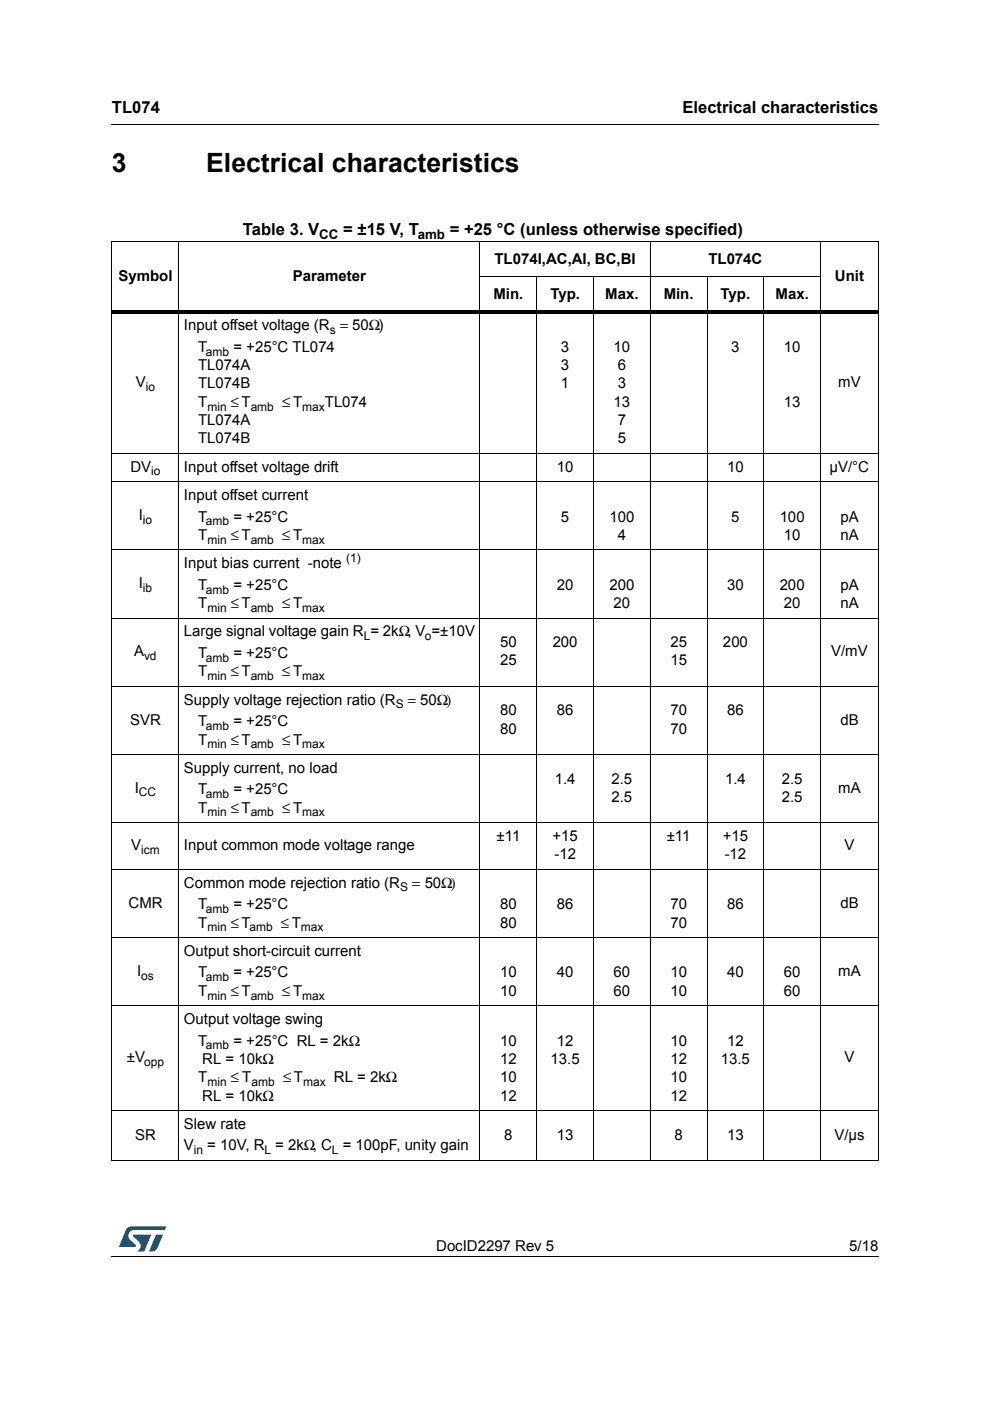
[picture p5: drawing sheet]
<svg xmlns="http://www.w3.org/2000/svg" width="210mm" height="297mm" viewBox="0 0 210 297" stroke-linecap="round" stroke-linejoin="round" font-family="sans-serif">
<defs><g id="words">
<g font-size="5.6">
<text x="23.7" y="36.4">3</text>
<text x="43.7" y="36.4">Electrical characteristics</text>
</g>
<g font-size="3.5">
<text x="23.7" y="23.9">TL074</text>
<text x="144.7" y="23.9">Electrical characteristics</text>
<text x="51.5" y="49.8">Table 3. V</text>
<text x="72.8" y="49.8">= ±15 V, T</text>
<text x="95.4" y="49.8">= +25 °C (unless otherwise specified)</text>
</g>
<g font-size="3.2">
<text x="25.1" y="59.6">Symbol</text>
<text x="62.1" y="59.6">Parameter</text>
<text x="104.8" y="55.9">TL074I,AC,AI, BC,BI</text>
<text x="150.2" y="55.9">TL074C</text>
<text x="177" y="59.6">Unit</text>
<text x="104.6" y="63.3">Min.</text>
<text x="116.7" y="63.3">Typ.</text>
<text x="128.3" y="63.3">Max.</text>
<text x="140.7" y="63.3">Min.</text>
<text x="152.8" y="63.3">Typ.</text>
<text x="164.5" y="63.3">Max.</text>
<text x="39" y="70">Input offset voltage (R = 50Ω)</text>
<text x="42" y="74.6">T</text>
<text x="49.5" y="74.6">= +25°C TL074</text>
<text x="118.9" y="74.6">3</text>
<text x="130.1" y="74.6">10</text>
<text x="155" y="74.6">3</text>
<text x="166.2" y="74.6">10</text>
<text x="28.8" y="82">V</text>
<text x="42" y="78.5">TL074A</text>
<text x="42" y="82.4">TL074B</text>
<text x="118.9" y="78.5">3</text>
<text x="118.9" y="82.4">1</text>
<text x="131" y="78.5">6</text>
<text x="131" y="82.4">3</text>
<text x="177.7" y="82">mV</text>
<text x="42" y="86.2">T</text>
<text x="48.9" y="86.2">≤ T</text>
<text x="59.8" y="86.2">≤ T</text>
<text x="68.9" y="86.2">TL074</text>
<text x="130.1" y="86.2">13</text>
<text x="166.2" y="86.2">13</text>
<text x="42" y="90.1">TL074A</text>
<text x="42" y="94">TL074B</text>
<text x="131" y="90.1">7</text>
<text x="131" y="94">5</text>
<text x="27.7" y="100">DV</text>
<text x="39" y="100">Input offset voltage drift</text>
<text x="118.1" y="100">10</text>
<text x="154.2" y="100">10</text>
<text x="175.9" y="100">µV/°C</text>
<text x="39" y="106">Input offset current</text>
<text x="29.4" y="110.2">I</text>
<text x="42" y="110.6">T</text>
<text x="49.5" y="110.6">= +25°C</text>
<text x="118.9" y="110.6">5</text>
<text x="129.2" y="110.6">100</text>
<text x="155" y="110.6">5</text>
<text x="165.3" y="110.6">100</text>
<text x="178.2" y="110.6">pA</text>
<text x="42" y="114.5">T</text>
<text x="48.9" y="114.5">≤ T</text>
<text x="59.8" y="114.5">≤ T</text>
<text x="131" y="114.5">4</text>
<text x="166.2" y="114.5">10</text>
<text x="178.2" y="114.5">nA</text>
<text x="29.4" y="124.7">I</text>
<text x="39" y="120.5">Input bias current -note</text>
<text x="42" y="125.1">T</text>
<text x="49.5" y="125.1">= +25°C</text>
<text x="118.1" y="125.1">20</text>
<text x="129.2" y="125.1">200</text>
<text x="154.2" y="125.1">30</text>
<text x="165.3" y="125.1">200</text>
<text x="178.2" y="125.1">pA</text>
<text x="42" y="128.9">T</text>
<text x="48.9" y="128.9">≤ T</text>
<text x="59.8" y="128.9">≤ T</text>
<text x="130.1" y="128.9">20</text>
<text x="166.2" y="128.9">20</text>
<text x="178.2" y="128.9">nA</text>
<text x="39" y="134.9">Large signal voltage gain R = 2kΩ, V =±10V</text>
<text x="106" y="137.2">50</text>
<text x="117.2" y="137.2">200</text>
<text x="142.1" y="137.2">25</text>
<text x="153.3" y="137.2">200</text>
<text x="28.5" y="139.1">A</text>
<text x="42" y="143.4">T</text>
<text x="42" y="139.5">T</text>
<text x="48.9" y="143.4">≤ T</text>
<text x="49.5" y="139.5">= +25°C</text>
<text x="59.8" y="143.4">≤ T</text>
<text x="106" y="141.1">25</text>
<text x="142.1" y="141.1">15</text>
<text x="176.2" y="139.1">V/mV</text>
<text x="39" y="149.4">Supply voltage rejection ratio (R</text>
<text x="86.5" y="149.4">= 50Ω)</text>
<text x="27.6" y="153.6">SVR</text>
<text x="42" y="154">T</text>
<text x="49.5" y="154">= +25°C</text>
<text x="106" y="151.7">80</text>
<text x="106" y="155.6">80</text>
<text x="118.1" y="151.7">86</text>
<text x="142.1" y="151.7">70</text>
<text x="142.1" y="155.6">70</text>
<text x="154.2" y="151.7">86</text>
<text x="178.2" y="153.6">dB</text>
<text x="42" y="157.9">T</text>
<text x="48.9" y="157.9">≤ T</text>
<text x="59.8" y="157.9">≤ T</text>
<text x="39" y="163.9">Supply current, no load</text>
<text x="117.6" y="166.1">1.4</text>
<text x="129.6" y="166.1">2.5</text>
<text x="153.7" y="166.1">1.4</text>
<text x="165.8" y="166.1">2.5</text>
<text x="28.6" y="168.1">I</text>
<text x="42" y="172.3">T</text>
<text x="42" y="168.4">T</text>
<text x="48.9" y="172.3">≤ T</text>
<text x="49.5" y="168.4">= +25°C</text>
<text x="59.8" y="172.3">≤ T</text>
<text x="129.6" y="170">2.5</text>
<text x="165.8" y="170">2.5</text>
<text x="177.7" y="168.1">mA</text>
<text x="105.3" y="178.3">±11</text>
<text x="117.1" y="178.3">+15</text>
<text x="141.4" y="178.3">±11</text>
<text x="153.2" y="178.3">+15</text>
<text x="27.8" y="180.3">V</text>
<text x="39" y="180.3">Input common mode voltage range</text>
<text x="117.5" y="182.2">-12</text>
<text x="153.6" y="182.2">-12</text>
<text x="179" y="180.3">V</text>
<text x="39" y="188.2">Common mode rejection ratio (R</text>
<text x="87.4" y="188.2">= 50Ω)</text>
<text x="27.2" y="192.4">CMR</text>
<text x="42" y="196.7">T</text>
<text x="42" y="192.8">T</text>
<text x="48.9" y="196.7">≤ T</text>
<text x="49.5" y="192.8">= +25°C</text>
<text x="59.6" y="196.7">≤ T</text>
<text x="106" y="192.8">80</text>
<text x="106" y="196.7">80</text>
<text x="118.1" y="192.8">86</text>
<text x="142.1" y="192.8">70</text>
<text x="142.1" y="196.7">70</text>
<text x="154.2" y="192.8">86</text>
<text x="178.2" y="192.4">dB</text>
<text x="39" y="202.6">Output short-circuit current</text>
<text x="29.1" y="206.9">I</text>
<text x="42" y="207.2">T</text>
<text x="49.5" y="207.2">= +25°C</text>
<text x="106" y="207.2">10</text>
<text x="118.1" y="207.2">40</text>
<text x="130.1" y="207.2">60</text>
<text x="142.1" y="207.2">10</text>
<text x="154.2" y="207.2">40</text>
<text x="166.2" y="207.2">60</text>
<text x="177.7" y="206.9">mA</text>
<text x="42" y="211.1">T</text>
<text x="48.9" y="211.1">≤ T</text>
<text x="59.8" y="211.1">≤ T</text>
<text x="106" y="211.1">10</text>
<text x="130.1" y="211.1">60</text>
<text x="142.1" y="211.1">10</text>
<text x="166.2" y="211.1">60</text>
<text x="39" y="217.1">Output voltage swing</text>
<text x="42" y="221.7">T</text>
<text x="49.5" y="221.7">= +25°C RL = 2kΩ</text>
<text x="106" y="221.7">10</text>
<text x="118.1" y="221.7">12</text>
<text x="142.1" y="221.7">10</text>
<text x="154.2" y="221.7">12</text>
<text x="26.9" y="225.2">±V</text>
<text x="42.9" y="225.6">RL = 10kΩ</text>
<text x="106" y="225.6">12</text>
<text x="116.7" y="225.6">13.5</text>
<text x="142.1" y="225.6">12</text>
<text x="152.8" y="225.6">13.5</text>
<text x="179" y="225.2">V</text>
<text x="42" y="229.5">T</text>
<text x="42.9" y="233.3">RL = 10kΩ</text>
<text x="48.9" y="229.5">≤ T</text>
<text x="60" y="229.5">≤ T</text>
<text x="70.8" y="229.5">RL = 2kΩ</text>
<text x="106" y="229.5">10</text>
<text x="106" y="233.3">12</text>
<text x="142.1" y="229.5">10</text>
<text x="142.1" y="233.3">12</text>
<text x="39" y="239.4">Slew rate</text>
<text x="28.6" y="241.6">SR</text>
<text x="39" y="243.9">V</text>
<text x="43.9" y="243.9">= 10V, R</text>
<text x="58.4" y="243.9">= 2kΩ, C</text>
<text x="72.7" y="243.9">= 100pF, unity gain</text>
<text x="106.9" y="241.6">8</text>
<text x="118.1" y="241.6">13</text>
<text x="143" y="241.6">8</text>
<text x="154.2" y="241.6">13</text>
<text x="176.9" y="241.6">V/µs</text>
<text x="92.5" y="265.1">DocID2297 Rev 5</text>
<text x="180.1" y="265.1">5/18</text>
</g>
<g font-size="2.8">
<text x="67.7" y="50.7">CC</text>
<text x="88.6" y="50.7">amb</text>
</g>
<g font-size="2.5">
<text x="69.9" y="70.8">s</text>
<text x="43.7" y="75.4">amb</text>
<text x="30.9" y="82.8">io</text>
<text x="44" y="87">min</text>
<text x="53.1" y="87">amb</text>
<text x="64.1" y="87">max</text>
<text x="32.1" y="100.8">io</text>
<text x="30.3" y="111">io</text>
<text x="43.7" y="111.4">amb</text>
<text x="44" y="115.3">min</text>
<text x="53.1" y="115.3">amb</text>
<text x="64.1" y="115.3">max</text>
<text x="73.4" y="119.2">(1)</text>
<text x="30.3" y="125.5">ib</text>
<text x="43.7" y="125.8">amb</text>
<text x="44" y="129.7">min</text>
<text x="53.1" y="129.7">amb</text>
<text x="64.1" y="129.7">max</text>
<text x="77.1" y="135.7">L</text>
<text x="90.1" y="135.7">o</text>
<text x="30.5" y="140">vd</text>
<text x="43.7" y="140.3">amb</text>
<text x="44" y="144.2">min</text>
<text x="53.1" y="144.2">amb</text>
<text x="64.1" y="144.2">max</text>
<text x="43.7" y="154.8">amb</text>
<text x="83.9" y="150.2">S</text>
<text x="44" y="158.6">min</text>
<text x="53.1" y="158.6">amb</text>
<text x="64.1" y="158.6">max</text>
<text x="29.5" y="168.9">CC</text>
<text x="43.7" y="169.2">amb</text>
<text x="44" y="173.1">min</text>
<text x="53.1" y="173.1">amb</text>
<text x="64.1" y="173.1">max</text>
<text x="29.9" y="181">icm</text>
<text x="84.8" y="189">S</text>
<text x="43.7" y="193.6">amb</text>
<text x="44" y="197.5">min</text>
<text x="52.9" y="197.5">amb</text>
<text x="63.8" y="197.5">max</text>
<text x="30" y="207.7">os</text>
<text x="43.7" y="208">amb</text>
<text x="44" y="211.9">min</text>
<text x="53.1" y="211.9">amb</text>
<text x="64.1" y="211.9">max</text>
<text x="30.6" y="226">opp</text>
<text x="43.7" y="222.5">amb</text>
<text x="44" y="230.3">min</text>
<text x="53.3" y="230.3">amb</text>
<text x="64.3" y="230.3">max</text>
<text x="41.1" y="244.7">in</text>
<text x="56.1" y="244.7">L</text>
<text x="70.4" y="244.7">L</text>
</g>
</g></defs>
<path d="M23.6 26.2l.1 .2zM23.6 266.3l.1 .1z" fill="#000"/>
<path d="M23.7 26.3h162.6M23.7 266.3h162.6" fill="none" stroke="#000" stroke-width=".21"/>
<path d="M25.2 260h10v5.3h-10z" fill="#fff"/>
<g fill="#005189">
<path d="M26.9 260.5l1-.5 7.3 .1-.3 .7h-6.4a1.31 1.31 0 0 0-1.3 1.1 1.31 1.31 0 0 0 .8 1.4l.7 .7 .1 .3-3.5 .1z"/>
<path d="M33.1 261.8h1.4l-.6 1.6a2.16 2.16 0 0 1-1.3 1.9l-1-.1z"/>
<path d="M28.3 261.8l3.7 .1-1.4 3.3-1.5 .1a1.43 1.43 0 0 0 .6-1.7l-1.4-1.4z"/>
</g>
<g fill="none" stroke="#000" stroke-width=".21">
<path d="M23.6 51.3h162.7M23.7 51.4v194.6M38 51.2v194.9M101.7 58.7h72.4M101.8 51.2v194.9M113.8 58.6v187.5M125.8 58.6v187.5M137.9 51.2v194.9M149.9 58.6v187.5M161.9 58.6v187.5M174 51.2v194.9M186.2 51.4v194.6"/>
<path d="M23.6 96.1h162.7M23.6 102.1h162.7M23.6 116.6h162.7M23.6 131h162.7M23.6 145.5h162.7M23.6 160h162.7M23.6 174.4h162.7M23.6 184.3h162.7M23.6 198.8h162.7M23.6 213.2h162.7M23.6 235.5h162.7M23.6 246h162.7"/>
</g>
<path d="M23.6 65.8h162.7v.7h-162.7z" fill="#000"/>
<use href="#words"/>
</svg>
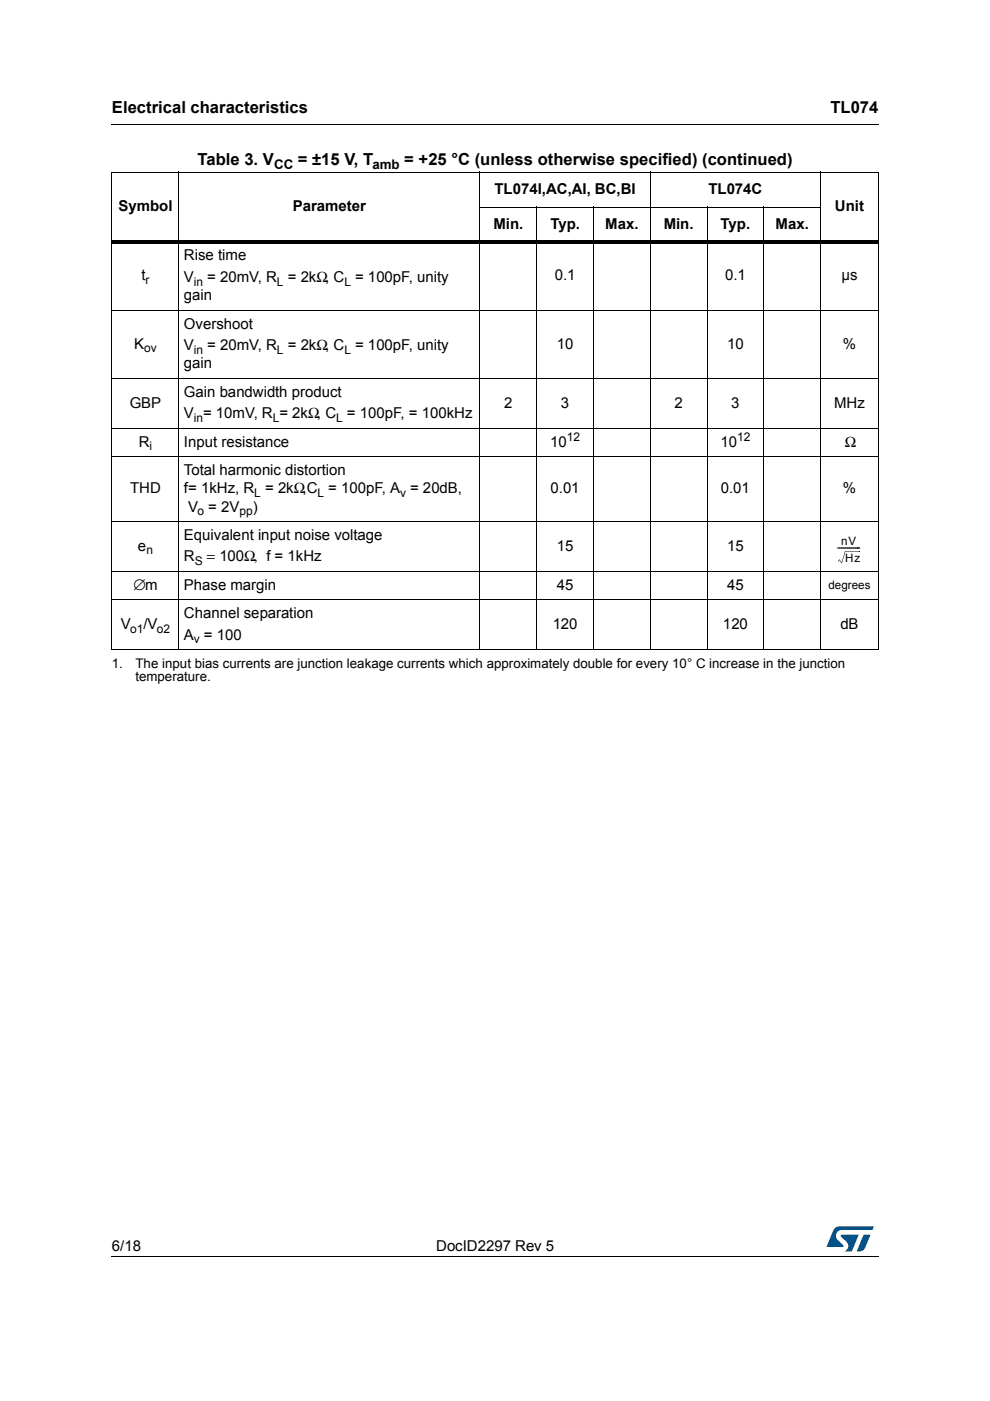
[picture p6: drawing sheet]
<svg xmlns="http://www.w3.org/2000/svg" width="210mm" height="297mm" viewBox="0 0 210 297" stroke-linecap="round" stroke-linejoin="round" font-family="sans-serif">
<defs><g id="words">
<g font-size="3.5">
<text x="23.7" y="23.9">Electrical characteristics</text>
<text x="176.1" y="23.9">TL074</text>
<text x="41.9" y="35">Table 3. V</text>
<text x="63.1" y="35">= ±15 V, T</text>
<text x="85.7" y="35">= +25 °C (unless otherwise specified) (continued)</text>
</g>
<g font-size="3.2">
<text x="104.8" y="41.1">TL074I,AC,AI, BC,BI</text>
<text x="150.2" y="41.1">TL074C</text>
<text x="25.1" y="44.8">Symbol</text>
<text x="62.1" y="44.8">Parameter</text>
<text x="177" y="44.8">Unit</text>
<text x="104.6" y="48.5">Min.</text>
<text x="116.7" y="48.5">Typ.</text>
<text x="128.3" y="48.5">Max.</text>
<text x="140.7" y="48.5">Min.</text>
<text x="152.8" y="48.5">Typ.</text>
<text x="164.5" y="48.5">Max.</text>
<text x="30" y="59.4">t</text>
<text x="39" y="55.2">Rise time</text>
<text x="39" y="59.8">V</text>
<text x="43.9" y="59.8">= 20mV, R</text>
<text x="61" y="59.8">= 2kΩ, C</text>
<text x="75.3" y="59.8">= 100pF, unity</text>
<text x="117.6" y="59.4">0.1</text>
<text x="153.7" y="59.4">0.1</text>
<text x="178.4" y="59.4">µs</text>
<text x="39" y="63.6">gain</text>
<text x="39" y="69.7">Overshoot</text>
<text x="28.4" y="73.9">K</text>
<text x="39" y="74.2">V</text>
<text x="43.9" y="74.2">= 20mV, R</text>
<text x="61" y="74.2">= 2kΩ, C</text>
<text x="75.3" y="74.2">= 100pF, unity</text>
<text x="118.1" y="73.9">10</text>
<text x="154.2" y="73.9">10</text>
<text x="178.7" y="73.9">%</text>
<text x="39" y="78.1">gain</text>
<text x="27.5" y="86.4">GBP</text>
<text x="39" y="84.1">Gain bandwidth product</text>
<text x="39" y="88.7">V = 10mV, R = 2kΩ, C</text>
<text x="73.6" y="88.7">= 100pF, = 100kHz</text>
<text x="106.9" y="86.4">2</text>
<text x="118.9" y="86.4">3</text>
<text x="143" y="86.4">2</text>
<text x="155" y="86.4">3</text>
<text x="176.8" y="86.4">MHz</text>
<text x="29.4" y="94.7">R</text>
<text x="39" y="94.7">Input resistance</text>
<text x="116.6" y="94.7">10</text>
<text x="152.8" y="94.7">10</text>
<text x="179.1" y="94.7">Ω</text>
<text x="39" y="100.7">Total harmonic distortion</text>
<text x="27.6" y="104.6">THD</text>
<text x="39" y="104.6">f= 1kHz, R</text>
<text x="56.2" y="104.6">= 2kΩ,C</text>
<text x="69.6" y="104.6">= 100pF, A = 20dB,</text>
<text x="116.7" y="104.6">0.01</text>
<text x="152.8" y="104.6">0.01</text>
<text x="178.7" y="104.6">%</text>
<text x="39.9" y="108.5">V = 2V</text>
<text x="53.6" y="108.5">)</text>
<text x="29.3" y="116.8">e</text>
<text x="39" y="114.5">Equivalent input noise voltage</text>
<text x="39" y="119">R</text>
<text x="43.9" y="119">= 100Ω, f = 1kHz</text>
<text x="118.1" y="116.8">15</text>
<text x="154.2" y="116.8">15</text>
<text x="28.3" y="125.1">∅m</text>
<text x="39" y="125.1">Phase margin</text>
<text x="118.1" y="125.1">45</text>
<text x="154.2" y="125.1">45</text>
<text x="39" y="131">Channel separation</text>
<text x="25.6" y="133.3">V</text>
<text x="30.4" y="133.3">/V</text>
<text x="39" y="135.6">A = 100</text>
<text x="117.2" y="133.3">120</text>
<text x="153.3" y="133.3">120</text>
<text x="178.2" y="133.3">dB</text>
<text x="23.7" y="265.1">6/18</text>
<text x="92.5" y="265.1">DocID2297 Rev 5</text>
</g>
<g font-size="2.8">
<text x="58.1" y="35.8">CC</text>
<text x="79" y="35.8">amb</text>
<text x="23.7" y="141.6">1.</text>
<text x="28.7" y="141.6">The input bias currents are junction leakage currents which approximately double for every 10° C increase in the junction</text>
<text x="28.7" y="144.4">temperature.</text>
</g>
<g font-size="2.5">
<text x="30.9" y="60.2">r</text>
<text x="41.1" y="60.6">in</text>
<text x="58.7" y="60.6">L</text>
<text x="73" y="60.6">L</text>
<text x="30.6" y="74.7">ov</text>
<text x="41.1" y="75">in</text>
<text x="58.7" y="75">L</text>
<text x="73" y="75">L</text>
<text x="41.1" y="89.5">in</text>
<text x="57.8" y="89.5">L</text>
<text x="71.2" y="89.5">L</text>
<text x="31.7" y="95.5">i</text>
<text x="120.2" y="93.4">12</text>
<text x="156.3" y="93.4">12</text>
<text x="53.9" y="105.4">L</text>
<text x="67.3" y="105.4">L</text>
<text x="84.8" y="105.4">v</text>
<text x="41.9" y="109.3">o</text>
<text x="50.8" y="109.3">pp</text>
<text x="31" y="117.5">n</text>
<text x="41.3" y="119.8">S</text>
<text x="177.5" y="116.8">-----------</text>
<text x="178.3" y="115.5">nV</text>
<text x="179.2" y="119.1">Hz</text>
<text x="175.7" y="124.9">degrees</text>
<text x="27.6" y="134.1">o1</text>
<text x="33.3" y="134.1">o2</text>
<text x="41.1" y="136.4">v</text>
</g>
</g></defs>
<path d="M23.6 26.2l.1 .2zM23.6 266.3l.1 .1z" fill="#000"/>
<path d="M23.7 26.3h162.6M23.7 266.3h162.6" fill="none" stroke="#000" stroke-width=".21"/>
<path d="M175.3 260h10v5.3h-10z" fill="#fff"/>
<g fill="#005189">
<path d="M176.9 260.5l1-.5 7.4 .1-.4 .7h-6.4a1.31 1.31 0 0 0-1.2 1.1 1.31 1.31 0 0 0 .8 1.4l.7 .7v.3l-3.5 .1z"/>
<path d="M183.1 261.8h1.4l-.6 1.6a2.16 2.16 0 0 1-1.3 1.9l-.9-.1z"/>
<path d="M178.3 261.8l3.7 .1-1.3 3.3-1.6 .1a1.43 1.43 0 0 0 .6-1.7l-1.4-1.4z"/>
</g>
<g fill="none" stroke="#000" stroke-width=".21">
<path d="M23.6 36.5h162.7M23.7 36.6v101M38 36.4v101.4M101.8 36.4v101.4M137.9 36.4v101.4M174 36.4v101.4M186.2 36.6v101M101.7 43.9h72.4M113.8 43.8v94M125.8 43.8v94M149.9 43.8v94M161.9 43.8v94"/>
<path d="M23.6 65.8h162.7M23.6 80.2h162.7M23.6 90.8h162.7M23.6 96.8h162.7M23.6 110.6h162.7M179.2 116.9h3M23.6 121.2h162.7M23.6 127.2h162.7M23.6 137.8h162.7"/>
</g>
<path d="M23.6 51h162.7v.7h-162.7zM177.7 119v.1zM177.9 118.6l-.1 .4zM178.4 119.4h.1zM178 118.6l.4 .8zM179.2 116.9h.1l-.8 2.5h-.1zM182.2 116.8v.1z" fill="#000"/>
<use href="#words"/>
</svg>
